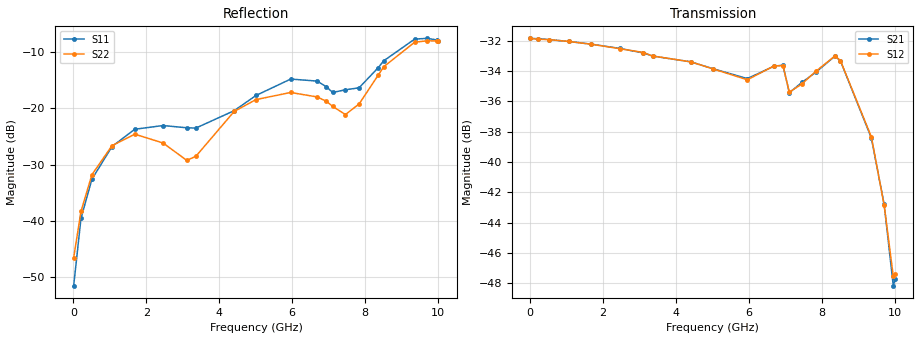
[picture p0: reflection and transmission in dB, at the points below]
! Device ID: PE43704
! Dir: z:\PE43704\PE43704_Char_1_20130516\PE43704\AMB\3p400V\31p00dB
! Serial: 14
! Insertion: A
! Impedance: 50 ohm
! Temp: Amb
! VDD: 3.400V
! Attenuation Step: 31.00dB
! IDD: 1.139707e-01mA
#  Hz  S  RI  R  50
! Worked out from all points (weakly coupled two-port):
!   401 points, 10 MHz to 10.01 GHz, reference 50 ohm
!   highest |S21| = -31.84 dB at 10 MHz (marker M1); lowest = -48.2 dB at 9.96 GHz (marker M2)
!   lowest |S11| = -51.6 dB at 10 MHz (marker M3), VSWR 1.01, Z = 50.3 + j0.0485 ohm
!   |S11| at or under -10 dB: start of sweep to 8.725 GHz
!   |S22| runs from -46.6 to -7.9 dB; largest |S21 - S12| = 0.00067
!   S11 on the Smith chart (normalised r, x): 10 MHz: 1.01, +0.00; 7.46 GHz: 0.79, +0.15; 8.51 GHz: 0.81, +0.46; 9.36 GHz: 0.54, +0.49; 10.01 GHz: 0.47, +0.28
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1e7  0.00259 0.000482  0.0256 -7.16e-05  0.0256 -4.65e-06  -0.00465 0.000474
2.1e8  0.00128 0.0104  0.0255 -0.00125  0.0254 -0.00124  -0.00542 0.0108
5.1e8  -0.00677 0.0224  0.0252 -0.00295  0.0252 -0.00294  -0.0127 0.0223
1.06e9  -0.0346 0.0299  0.0243 -0.00589  0.0243 -0.00587  -0.0367 0.0286
1.685e9  -0.0632 0.0161  0.0228 -0.00895  0.0228 -0.00892  -0.0573 0.0138
2.46e9  -0.0702 -0.00498  0.0204 -0.0121  0.0204 -0.012  -0.0492 -0.000599
3.11e9  -0.067 -0.00528  0.0179 -0.0143  0.018 -0.0143  -0.0333 0.00881
3.36e9  -0.0668 0.000497  0.0167 -0.0149  0.0168 -0.0148  -0.0333 0.0171
4.41e9  -0.084 0.0453  0.0134 -0.0167  0.0134 -0.0167  -0.0748 0.0569
5.01e9  -0.1076 0.0739  0.0116 -0.0167  0.0117 -0.0166  -0.1056 0.0568
5.96e9  -0.1546 0.0971  0.00836 -0.0169  0.00838 -0.0167  -0.1314 0.0441
6.685e9  -0.1542 0.083  0.00749 -0.0193  0.00761 -0.0193  -0.1216 0.0349
6.935e9  -0.1368 0.0751  0.00446 -0.0204  0.00418 -0.0204  -0.1088 0.0397
7.11e9  -0.1229 0.0644  0.00332 -0.0166  0.00316 -0.0167  -0.0934 0.0464
7.46e9  -0.1125 0.0938  0.00438 -0.0178  0.0043 -0.0176  -0.0661 0.0583
7.835e9  -0.0657 0.1378  0.00428 -0.0193  0.0045 -0.0194  -0.0522 0.0962
8.36e9  -0.0334 0.2282  -0.00265 -0.0222  -0.00293 -0.0222  -0.0719 0.1847
8.51e9  -0.036 0.263  -0.00544 -0.0209  -0.00519 -0.021  -0.0871 0.2182
9.36e9  -0.1785 0.3743  -0.00878 -0.00816  -0.00891 -0.00818  -0.2508 0.2978
9.71e9  -0.2589 0.3316  -0.00518 -0.00506  -0.00523 -0.00495  -0.3251 0.2329
9.96e9  -0.3059 0.2689  -0.00121 -0.00371  -0.00127 -0.004  -0.3678 0.1558
1.001e10  -0.3135 0.2498  -0.000536 -0.00406  -0.000678 -0.00421  -0.3724 0.1357
